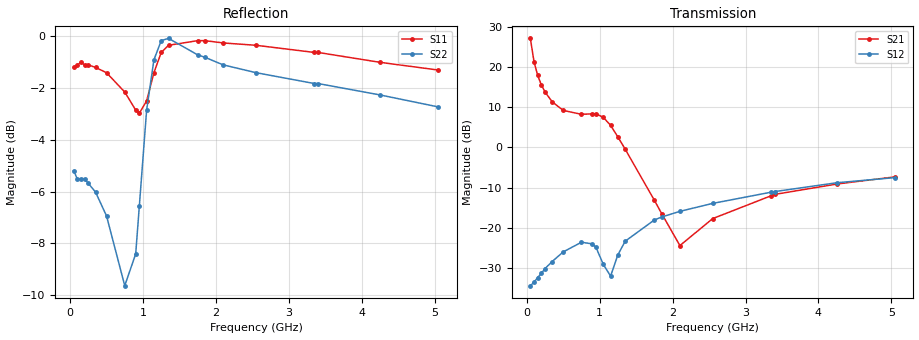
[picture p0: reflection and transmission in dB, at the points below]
!AT-33225
!S-PARAMETERS at Vce=4.8V  Ic=150mA.  LAST UPDATED 08-05-96
# ghz s ma r 50
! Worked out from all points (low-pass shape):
!   101 points, 50 MHz to 5.05 GHz, reference 50 ohm
!   highest |S21| = 27.14 dB at 50 MHz (marker M1); lowest = -24.4 dB at 2.1 GHz (marker M2)
!   |S21| within 3 dB of the highest: start of sweep to 75.92 MHz
!   lowest |S11| = -3.0 dB at 950 MHz (marker M3), VSWR 5.90, Z = 8.5 + j2.54 ohm
!   |S11| at or under -10 dB: nowhere
!   |S22| runs from -10.2 to -0.1 dB; largest |S21 - S12| = 23
!   S11 on the Smith chart (normalised r, x): 50 MHz: 0.07, -0.16; 500 MHz: 0.08, +0.07; 1.15 GHz: 0.08, -0.01; 1.85 GHz: 0.01, +0.17; 3.35 GHz: 0.04, +0.36; 5.05 GHz: 0.10, +0.60
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0.05  0.87 -162.0  22.76 100.0  0.019 25.0  0.55 -149.0
0.1  0.88 -172.0  11.69 91.0  0.021 30.0  0.53 -166.0
0.15  0.89 -177.0  7.89 86.0  0.024 36.0  0.53 -172.0
0.2  0.88 -179.0  6.02 82.0  0.027 41.0  0.53 -176.0
0.25  0.88 179.0  4.91 78.0  0.031 44.0  0.52 -178.0
0.35  0.87 176.0  3.69 72.0  0.038 49.0  0.5 179.0
0.5  0.85 172.0  2.89 61.0  0.05 49.0  0.45 177.0
0.75  0.78 169.0  2.58 37.0  0.066 39.0  0.33 -171.0
0.9  0.72 172.0  2.62 13.0  0.063 26.0  0.38 -138.0
0.95  0.71 174.0  2.61 2.0  0.057 21.0  0.47 -132.0
1.05  0.75 -180.0  2.37 -22.0  0.035 19.0  0.72 -136.0
1.15  0.85 -179.0  1.88 -46.0  0.025 69.0  0.9 -149.0
1.25  0.93 177.0  1.35 -66.0  0.046 93.0  0.98 -161.0
1.35  0.96 174.0  0.95 -81.0  0.068 92.0  0.99 -170.0
1.75  0.98 163.0  0.22 -119.0  0.125 78.0  0.92 171.0
1.85  0.98 161.0  0.15 -131.0  0.136 76.0  0.91 168.0
2.1  0.97 157.0  0.06 163.0  0.16 70.0  0.88 162.0
2.55  0.96 151.0  0.13 80.0  0.201 62.0  0.85 153.0
3.35  0.93 140.0  0.25 53.0  0.277 50.0  0.81 137.0
3.4  0.93 140.0  0.26 53.0  0.282 49.0  0.81 136.0
4.25  0.89 129.0  0.35 34.0  0.363 32.0  0.77 117.0
5.05  0.86 118.0  0.43 17.0  0.421 17.0  0.73 95.0
